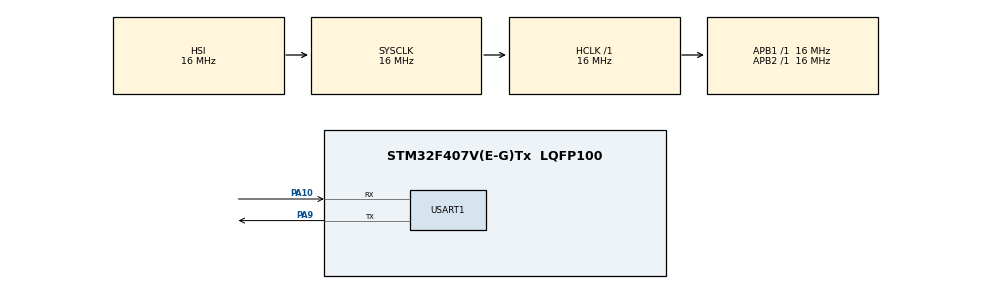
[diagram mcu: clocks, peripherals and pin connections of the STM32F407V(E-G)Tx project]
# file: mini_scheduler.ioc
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Mcu.Family=STM32F4
Mcu.Name=STM32F407V(E-G)Tx
Mcu.Package=LQFP100
NVIC.PriorityGroup=NVIC_PRIORITYGROUP_4
NVIC.TIM1_UP_TIM10_IRQn=true\:15\:0\:false\:false\:true\:false\:true\:true
NVIC.TimeBase=TIM1_UP_TIM10_IRQn
NVIC.TimeBaseIP=TIM1
PA10.Mode=Asynchronous
PA10.Signal=USART1_RX
PA13.Mode=Serial_Wire
PA13.Signal=SYS_JTMS-SWDIO
PA14.Mode=Serial_Wire
PA14.Signal=SYS_JTCK-SWCLK
PA9.Mode=Asynchronous
PA9.Signal=USART1_TX
ProjectManager.HeapSize=0x200
ProjectManager.StackSize=0x400
ProjectManager.TargetToolchain=STM32CubeIDE
RCC.AHBFreq_Value=16000000
RCC.APB1Freq_Value=16000000
RCC.APB2Freq_Value=16000000
RCC.CortexFreq_Value=16000000
RCC.HSE_VALUE=25000000
RCC.HSI_VALUE=16000000
RCC.LSE_VALUE=32768
RCC.SYSCLKFreq_VALUE=16000000
RCC.VCOOutputFreq_Value=192000000
USART1.VirtualMode=VM_ASYNC
VP_SYS_VS_tim1.Mode=TIM1
board=custom

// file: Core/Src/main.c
/* USER CODE BEGIN Header */
/**
  ******************************************************************************
  * @file           : main.c
  * @brief          : Main program body
  ******************************************************************************
  * @attention
  *
  * Copyright (c) 2025 STMicroelectronics.
  * All rights reserved.
  *
  * This software is licensed under terms that can be found in the LICENSE file
  * in the root directory of this software component.
  * If no LICENSE file comes with this software, it is provided AS-IS.
  *
  ******************************************************************************
  */
/* USER CODE END Header */
#include "main.h"
#include "time_slice.h"

UART_HandleTypeDef huart1;

void SystemClock_Config(void);
static void MX_GPIO_Init(void);
static void MX_USART1_UART_Init(void);

int main(void)
{

  /* MCU Configuration--------------------------------------------------------*/

  /* Reset of all peripherals, Initializes the Flash interface and the Systick. */
  HAL_Init();

  /* Configure the system clock */
  SystemClock_Config();

  /* Initialize all configured peripherals */
  MX_GPIO_Init();
  MX_USART1_UART_Init();
  timeSlice_initScheduler();
  /* Infinite loop */
  while (1)
  {
  }
}

void SystemClock_Config(void)
{
  RCC_OscInitTypeDef RCC_OscInitStruct = {0};
  RCC_ClkInitTypeDef RCC_ClkInitStruct = {0};

  /** Configure the main internal regulator output voltage
  */
  __HAL_RCC_PWR_CLK_ENABLE();
  __HAL_PWR_VOLTAGESCALING_CONFIG(PWR_REGULATOR_VOLTAGE_SCALE1);

  /** Initializes the RCC Oscillators according to the specified parameters
  * in the RCC_OscInitTypeDef structure.
  */
  RCC_OscInitStruct.OscillatorType = RCC_OSCILLATORTYPE_HSI;
  RCC_OscInitStruct.HSIState = RCC_HSI_ON;
  RCC_OscInitStruct.HSICalibrationValue = RCC_HSICALIBRATION_DEFAULT;
  RCC_OscInitStruct.PLL.PLLState = RCC_PLL_NONE;
  if (HAL_RCC_OscConfig(&RCC_OscInitStruct) != HAL_OK)
  {
    Error_Handler();
  }

  /** Initializes the CPU, AHB and APB buses clocks
  */
  RCC_ClkInitStruct.ClockType = RCC_CLOCKTYPE_HCLK|RCC_CLOCKTYPE_SYSCLK
                              |RCC_CLOCKTYPE_PCLK1|RCC_CLOCKTYPE_PCLK2;
  RCC_ClkInitStruct.SYSCLKSource = RCC_SYSCLKSOURCE_HSI;
  RCC_ClkInitStruct.AHBCLKDivider = RCC_SYSCLK_DIV1;
  RCC_ClkInitStruct.APB1CLKDivider = RCC_HCLK_DIV1;
  RCC_ClkInitStruct.APB2CLKDivider = RCC_HCLK_DIV1;

  if (HAL_RCC_ClockConfig(&RCC_ClkInitStruct, FLASH_LATENCY_0) != HAL_OK)
  {
    Error_Handler();
  }
}

static void MX_USART1_UART_Init(void)
{

  huart1.Instance = USART1;
  huart1.Init.BaudRate = 115200;
  huart1.Init.WordLength = UART_WORDLENGTH_8B;
  huart1.Init.StopBits = UART_STOPBITS_1;
  huart1.Init.Parity = UART_PARITY_NONE;
  huart1.Init.Mode = UART_MODE_TX_RX;
  huart1.Init.HwFlowCtl = UART_HWCONTROL_NONE;
  huart1.Init.OverSampling = UART_OVERSAMPLING_16;
  if (HAL_UART_Init(&huart1) != HAL_OK)
  {
    Error_Handler();
  }

}

static void MX_GPIO_Init(void)
{

  /* GPIO Ports Clock Enable */
  __HAL_RCC_GPIOA_CLK_ENABLE();

  GPIO_InitTypeDef GPIO_InitStruct = {0};
  /* USER CODE BEGIN USART1_MspInit 0 */

    GPIO_InitStruct.Pin = GPIO_PIN_6|GPIO_PIN_7;
    GPIO_InitStruct.Mode = GPIO_MODE_OUTPUT_PP;
    GPIO_InitStruct.Pull = GPIO_NOPULL;
    GPIO_InitStruct.Speed = GPIO_SPEED_FREQ_VERY_HIGH;
    HAL_GPIO_Init(GPIOA, &GPIO_InitStruct);
}

void HAL_TIM_PeriodElapsedCallback(TIM_HandleTypeDef *htim)
{
  if (htim->Instance == TIM1) {
    HAL_IncTick();
  }
}

void Error_Handler(void)
{
  __disable_irq();
  while (1)
  {
  }
}
